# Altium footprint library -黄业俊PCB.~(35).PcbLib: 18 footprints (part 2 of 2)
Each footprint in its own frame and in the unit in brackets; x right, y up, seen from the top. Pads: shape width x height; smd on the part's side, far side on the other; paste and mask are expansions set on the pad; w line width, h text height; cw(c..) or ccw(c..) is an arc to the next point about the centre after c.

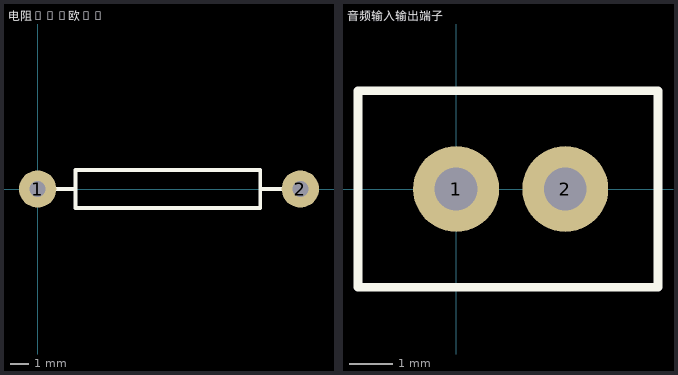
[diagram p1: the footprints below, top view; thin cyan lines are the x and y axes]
## 电阻2.2欧1W [mm]
pads (2):
  round 2 hole 0.85: 1(0,0) 2(14.097,0)
Top Overlay:
  lines w0.2: 1.016,0 2.032,0 ; 12.065,0 13.081,0 ; 2.032,-1.016 2.032,1.016 11.938,1.016 11.938,-1.016 2.032,-1.016

## 音频输入输出端子 [mm]
pads (2):
  round 2 hole 1: 1(0,0) 2(2.54,0)
Top Overlay:
  lines w0.2: -2.286,-2.286 -2.286,2.286 4.699,2.286 4.699,-2.286 -2.286,-2.286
